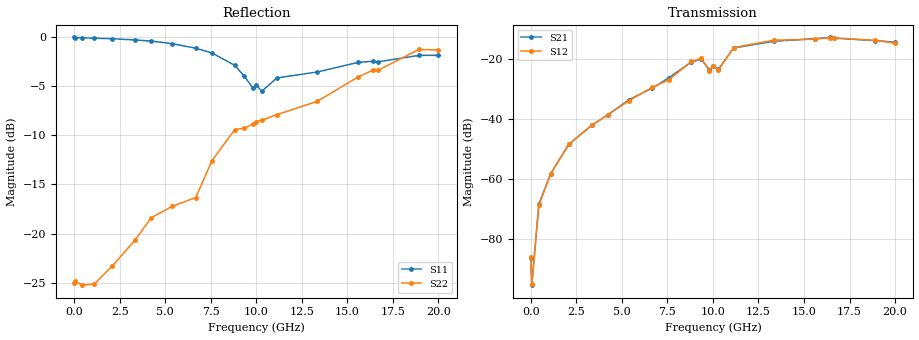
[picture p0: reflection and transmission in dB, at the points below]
! Integrated Device Technology
! Corporate Headquarters
! 6024 Silver Creek Valley Road
! San Jose, CA 95138  USA
! Phone:  1-408-284-8200
! Toll Free:  1-800-223-1366
! Webpage:  http://www.idt.com/
! Timing and RF Division
! 515 Groton Road, Suite 102
! Westford, MA 01886-6024
! Device:  F2910
! Description: Constant Impedance K|Z| SPST RF Switch
! Frequency:  0.030 - 8.000 GMHz
! Package:  2x2 mm DFN Plastic Package: 8 pin
! Ports:  2 RF, 2 DC
!  Pin  1  = NC
!  Pin  2  = GND
!  Pin  3  = GND
!  Pin  4  = NC
!  Pin  5  = RF1  = Port 1
!  Pin  6  = VDD
!  Pin  7  = V1
!  Pin  8  = RF2  = Port 2
! Voltage:  VCC  =  +3.30 Volts
! Current:  ICC  = 168  uA
! State:  OFF
! V1:  Logic LOW
! Data:  The device was measured on the F2910 evaluation board which has
!  individual transmission lines to the RF pins.  Data was collected
!  using a calibrated network analyzer.  The input lines were
!  modeled using Automatic Fixture Removal (AFR) from Keysight.
!  The reference plane is at the package pin.
!  data was collected with the high frequency option using capacitors
!  on Vcc and V1 pins.
! Misc:
!  Action Tracker AT0436
! Date Measured:  2018-12-14
! Date:  2018-12-14  MJV
! Note:
!  Integrated Device Technology supplies this data as a sample of measured
!  data at the evaluation board for this product.  Your particular data for this
!  product may vary.
!  Data was taken at 25 degrees C.
!  Integrated Device Technology reserves the right to change this data at anytime.
# Hz S dB R 50
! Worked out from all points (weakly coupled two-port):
!   2000 points, 10 MHz to 20 GHz, reference 50 ohm
!   highest |S21| = -12.95 dB at 16.4 GHz (marker M1); lowest = -95.4 dB at 60 MHz (marker M2)
!   lowest |S11| = -5.5 dB at 10.3 GHz (marker M3), VSWR 3.25, Z = 15.4 + j1.72 ohm
!   |S11| at or under -10 dB: nowhere
!   |S22| runs from -25.4 to -1.1 dB; largest |S21 - S12| = 0.013
!   S11 on the Smith chart (normalised r, x): 10 MHz: open; 4.24 GHz: 0.09, -1.63; 7.57 GHz: 0.11, -0.46; 11.14 GHz: 0.24, +0.15; 15.6 GHz: 0.38, +1.21; 20 GHz: 2.04, +3.75
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1e7  -0.05 -0.3  -86.52 19.2  -85.98 12.3  -24.99 -179.6
6e7  -0.07 -1.0  -95.38 25.5  -95.12 41.7  -24.85 178.6
4.5e8  -0.10 -6.3  -68.46 107.0  -68.78 108.0  -25.23 167.4
1.1e9  -0.13 -15.2  -58.27 123.6  -58.28 123.9  -25.12 154.7
2.1e9  -0.19 -28.8  -48.46 131.2  -48.49 131.0  -23.29 141.2
3.35e9  -0.31 -47.7  -42.23 131.9  -42.16 131.9  -20.65 139.9
4.24e9  -0.43 -62.8  -38.65 127.6  -38.68 127.8  -18.38 143.1
5.4e9  -0.69 -84.1  -33.67 126.3  -34.00 127.4  -17.21 140.7
6.68e9  -1.15 -109.6  -29.82 121.5  -29.53 125.5  -16.33 117.8
7.57e9  -1.63 -129.7  -26.42 116.9  -27.12 122.7  -12.58 111.4
8.82e9  -2.89 -161.7  -21.17 95.7  -20.93 97.7  -9.42 90.4
9.35e9  -4.01 -175.8  -20.13 73.7  -19.96 71.9  -9.27 82.8
9.81e9  -5.18 -179.2  -23.78 64.7  -24.00 63.8  -8.84 82.8
1.001e10  -4.90 177.9  -22.61 77.5  -22.41 77.0  -8.60 81.7
1.03e10  -5.52 175.6  -23.58 78.3  -23.81 78.5  -8.46 80.5
1.114e10  -4.17 161.7  -16.46 76.1  -16.34 74.0  -7.90 72.6
1.334e10  -3.57 113.7  -14.24 21.5  -13.88 22.1  -6.56 63.4
1.56e10  -2.59 75.7  -13.39 -15.5  -13.55 -14.0  -4.07 38.5
1.64e10  -2.48 64.6  -12.95 -27.1  -13.11 -28.0  -3.37 29.5
1.667e10  -2.54 61.1  -13.22 -33.0  -13.08 -32.6  -3.41 22.3
1.892e10  -1.88 34.3  -14.04 -62.3  -13.97 -62.4  -1.28 9.6
2e10  -1.87 23.5  -14.54 -75.2  -14.86 -76.8  -1.32 8.4
